###############################################################
#  Generated by:      Cadence Innovus 21.35-s114_1
#  OS:                Linux x86_64(Host ID pc231.ee.hacettepe.edu.tr)
#  Generated on:      Wed Dec 24 10:08:27 2025
#  Design:            mdu_macro
#  Command:           write_lef_abstract -5.7 outputs/mdu_macro/mdu_macro.lef
###############################################################

VERSION 5.7 ;

BUSBITCHARS "[]" ;
DIVIDERCHAR "/" ;

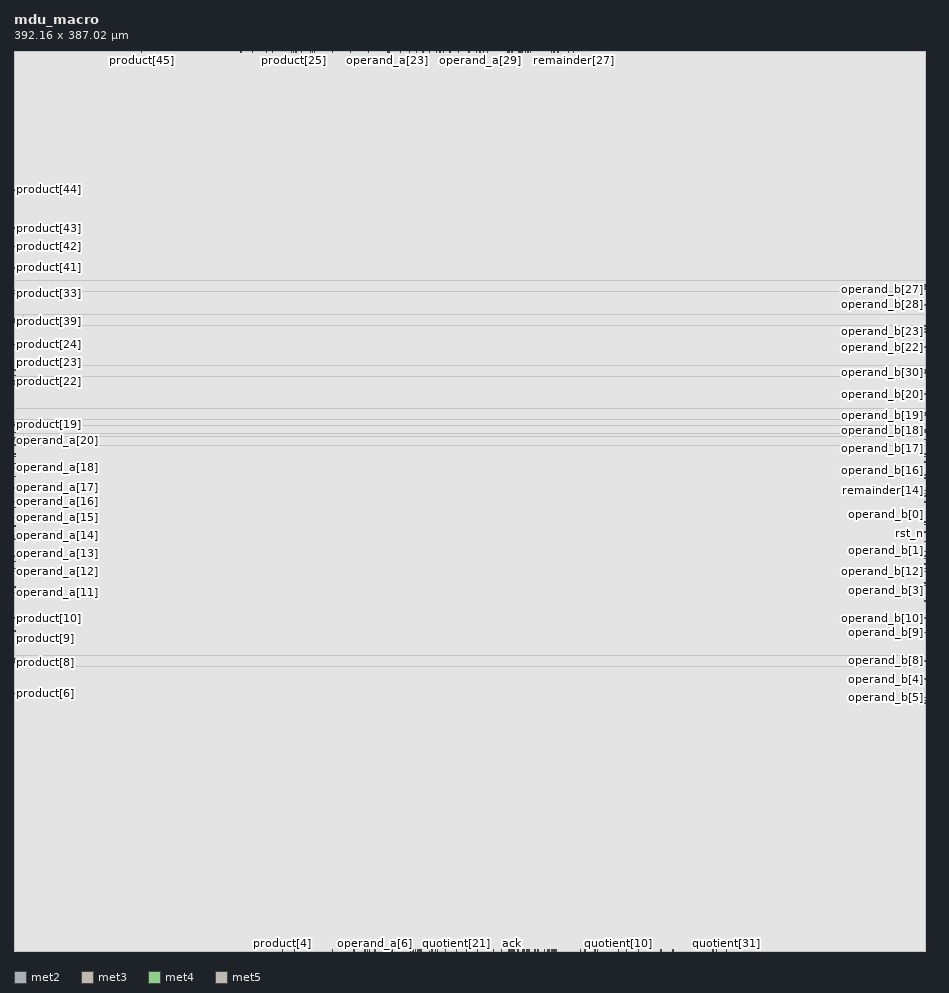
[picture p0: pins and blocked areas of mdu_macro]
MACRO mdu_macro
  CLASS BLOCK ;
  SIZE 392.160000 BY 387.020000 ;
  FOREIGN mdu_macro 0.000000 0.000000 ;
  ORIGIN 0 0 ;
  SYMMETRY X Y R90 ;
  PIN clk
    DIRECTION INPUT ;
    USE SIGNAL ;
    PORT
      LAYER met2 ;
        RECT 203.690000 386.535000 203.830000 387.020000 ;
    END
  END clk
  PIN rst_n
    DIRECTION INPUT ;
    USE SIGNAL ;
    PORT
      LAYER met3 ;
        RECT 391.360000 175.900000 392.160000 176.200000 ;
    END
  END rst_n
  PIN start
    DIRECTION INPUT ;
    USE SIGNAL ;
    PORT
      LAYER met3 ;
        RECT 391.360000 164.310000 392.160000 164.610000 ;
    END
  END start
  PIN ack
    DIRECTION INPUT ;
    USE SIGNAL ;
    PORT
      LAYER met2 ;
        RECT 214.250000 0.000000 214.390000 0.485000 ;
    END
  END ack
  PIN funct3[2]
    DIRECTION INPUT ;
    USE SIGNAL ;
    PORT
      LAYER met3 ;
        RECT 391.360000 180.170000 392.160000 180.470000 ;
    END
  END funct3[2]
  PIN funct3[1]
    DIRECTION INPUT ;
    USE SIGNAL ;
    PORT
      LAYER met3 ;
        RECT 391.360000 196.640000 392.160000 196.940000 ;
    END
  END funct3[1]
  PIN funct3[0]
    DIRECTION INPUT ;
    USE SIGNAL ;
    PORT
      LAYER met3 ;
        RECT 391.360000 195.420000 392.160000 195.720000 ;
    END
  END funct3[0]
  PIN operand_a[31]
    DIRECTION INPUT ;
    USE SIGNAL ;
    PORT
      LAYER met2 ;
        RECT 213.770000 386.535000 213.910000 387.020000 ;
    END
  END operand_a[31]
  PIN operand_a[30]
    DIRECTION INPUT ;
    USE SIGNAL ;
    PORT
      LAYER met2 ;
        RECT 178.730000 386.535000 178.870000 387.020000 ;
    END
  END operand_a[30]
  PIN operand_a[29]
    DIRECTION INPUT ;
    USE SIGNAL ;
    PORT
      LAYER met2 ;
        RECT 200.330000 386.535000 200.470000 387.020000 ;
    END
  END operand_a[29]
  PIN operand_a[28]
    DIRECTION INPUT ;
    USE SIGNAL ;
    PORT
      LAYER met2 ;
        RECT 195.530000 386.535000 195.670000 387.020000 ;
    END
  END operand_a[28]
  PIN operand_a[27]
    DIRECTION INPUT ;
    USE SIGNAL ;
    PORT
      LAYER met2 ;
        RECT 187.370000 386.535000 187.510000 387.020000 ;
    END
  END operand_a[27]
  PIN operand_a[26]
    DIRECTION INPUT ;
    USE SIGNAL ;
    PORT
      LAYER met2 ;
        RECT 183.050000 386.535000 183.190000 387.020000 ;
    END
  END operand_a[26]
  PIN operand_a[25]
    DIRECTION INPUT ;
    USE SIGNAL ;
    PORT
      LAYER met2 ;
        RECT 181.610000 386.535000 181.750000 387.020000 ;
    END
  END operand_a[25]
  PIN operand_a[24]
    DIRECTION INPUT ;
    USE SIGNAL ;
    PORT
      LAYER met2 ;
        RECT 166.250000 386.535000 166.390000 387.020000 ;
    END
  END operand_a[24]
  PIN operand_a[23]
    DIRECTION INPUT ;
    USE SIGNAL ;
    PORT
      LAYER met2 ;
        RECT 160.490000 386.535000 160.630000 387.020000 ;
    END
  END operand_a[23]
  PIN operand_a[22]
    DIRECTION INPUT ;
    USE SIGNAL ;
    PORT
      LAYER met4 ;
        RECT 160.605000 386.220000 160.905000 387.020000 ;
    END
  END operand_a[22]
  PIN operand_a[21]
    DIRECTION INPUT ;
    USE SIGNAL ;
    PORT
      LAYER met3 ;
        RECT 0.000000 225.920000 0.800000 226.220000 ;
    END
  END operand_a[21]
  PIN operand_a[20]
    DIRECTION INPUT ;
    USE SIGNAL ;
    PORT
      LAYER met3 ;
        RECT 0.000000 219.210000 0.800000 219.510000 ;
    END
  END operand_a[20]
  PIN operand_a[19]
    DIRECTION INPUT ;
    USE SIGNAL ;
    PORT
      LAYER met3 ;
        RECT 0.000000 212.500000 0.800000 212.800000 ;
    END
  END operand_a[19]
  PIN operand_a[18]
    DIRECTION INPUT ;
    USE SIGNAL ;
    PORT
      LAYER met3 ;
        RECT 0.000000 207.620000 0.800000 207.920000 ;
    END
  END operand_a[18]
  PIN operand_a[17]
    DIRECTION INPUT ;
    USE SIGNAL ;
    PORT
      LAYER met3 ;
        RECT 0.000000 199.080000 0.800000 199.380000 ;
    END
  END operand_a[17]
  PIN operand_a[16]
    DIRECTION INPUT ;
    USE SIGNAL ;
    PORT
      LAYER met3 ;
        RECT 0.000000 192.980000 0.800000 193.280000 ;
    END
  END operand_a[16]
  PIN operand_a[15]
    DIRECTION INPUT ;
    USE SIGNAL ;
    PORT
      LAYER met3 ;
        RECT 0.000000 186.270000 0.800000 186.570000 ;
    END
  END operand_a[15]
  PIN operand_a[14]
    DIRECTION INPUT ;
    USE SIGNAL ;
    PORT
      LAYER met3 ;
        RECT 0.000000 178.340000 0.800000 178.640000 ;
    END
  END operand_a[14]
  PIN operand_a[13]
    DIRECTION INPUT ;
    USE SIGNAL ;
    PORT
      LAYER met3 ;
        RECT 0.000000 167.360000 0.800000 167.660000 ;
    END
  END operand_a[13]
  PIN operand_a[12]
    DIRECTION INPUT ;
    USE SIGNAL ;
    PORT
      LAYER met3 ;
        RECT 0.000000 163.090000 0.800000 163.390000 ;
    END
  END operand_a[12]
  PIN operand_a[11]
    DIRECTION INPUT ;
    USE SIGNAL ;
    PORT
      LAYER met3 ;
        RECT 0.000000 153.940000 0.800000 154.240000 ;
    END
  END operand_a[11]
  PIN operand_a[10]
    DIRECTION INPUT ;
    USE SIGNAL ;
    PORT
      LAYER met2 ;
        RECT 151.850000 0.000000 151.990000 0.485000 ;
    END
  END operand_a[10]
  PIN operand_a[9]
    DIRECTION INPUT ;
    USE SIGNAL ;
    PORT
      LAYER met2 ;
        RECT 150.890000 0.000000 151.030000 0.485000 ;
    END
  END operand_a[9]
  PIN operand_a[8]
    DIRECTION INPUT ;
    USE SIGNAL ;
    PORT
      LAYER met2 ;
        RECT 159.530000 0.000000 159.670000 0.485000 ;
    END
  END operand_a[8]
  PIN operand_a[7]
    DIRECTION INPUT ;
    USE SIGNAL ;
    PORT
      LAYER met2 ;
        RECT 152.810000 0.000000 152.950000 0.485000 ;
    END
  END operand_a[7]
  PIN operand_a[6]
    DIRECTION INPUT ;
    USE SIGNAL ;
    PORT
      LAYER met2 ;
        RECT 155.210000 0.000000 155.350000 0.485000 ;
    END
  END operand_a[6]
  PIN operand_a[5]
    DIRECTION INPUT ;
    USE SIGNAL ;
    PORT
      LAYER met4 ;
        RECT 150.765000 0.000000 151.065000 0.800000 ;
    END
  END operand_a[5]
  PIN operand_a[4]
    DIRECTION INPUT ;
    USE SIGNAL ;
    PORT
      LAYER met2 ;
        RECT 162.410000 0.000000 162.550000 0.485000 ;
    END
  END operand_a[4]
  PIN operand_a[3]
    DIRECTION INPUT ;
    USE SIGNAL ;
    PORT
      LAYER met2 ;
        RECT 174.890000 0.000000 175.030000 0.485000 ;
    END
  END operand_a[3]
  PIN operand_a[2]
    DIRECTION INPUT ;
    USE SIGNAL ;
    PORT
      LAYER met2 ;
        RECT 181.130000 0.000000 181.270000 0.485000 ;
    END
  END operand_a[2]
  PIN operand_a[1]
    DIRECTION INPUT ;
    USE SIGNAL ;
    PORT
      LAYER met2 ;
        RECT 185.450000 0.000000 185.590000 0.485000 ;
    END
  END operand_a[1]
  PIN operand_a[0]
    DIRECTION INPUT ;
    USE SIGNAL ;
    PORT
      LAYER met2 ;
        RECT 194.570000 0.000000 194.710000 0.485000 ;
    END
  END operand_a[0]
  PIN operand_b[31]
    DIRECTION INPUT ;
    USE SIGNAL ;
    PORT
      LAYER met3 ;
        RECT 391.360000 219.820000 392.160000 220.120000 ;
    END
  END operand_b[31]
  PIN operand_b[30]
    DIRECTION INPUT ;
    USE SIGNAL ;
    PORT
      LAYER met3 ;
        RECT 391.360000 248.490000 392.160000 248.790000 ;
    END
  END operand_b[30]
  PIN operand_b[29]
    DIRECTION INPUT ;
    USE SIGNAL ;
    PORT
      LAYER met3 ;
        RECT 391.360000 267.400000 392.160000 267.700000 ;
    END
  END operand_b[29]
  PIN operand_b[28]
    DIRECTION INPUT ;
    USE SIGNAL ;
    PORT
      LAYER met3 ;
        RECT 391.360000 277.770000 392.160000 278.070000 ;
    END
  END operand_b[28]
  PIN operand_b[27]
    DIRECTION INPUT ;
    USE SIGNAL ;
    PORT
      LAYER met3 ;
        RECT 391.360000 284.480000 392.160000 284.780000 ;
    END
  END operand_b[27]
  PIN operand_b[26]
    DIRECTION INPUT ;
    USE SIGNAL ;
    PORT
      LAYER met3 ;
        RECT 391.360000 285.700000 392.160000 286.000000 ;
    END
  END operand_b[26]
  PIN operand_b[25]
    DIRECTION INPUT ;
    USE SIGNAL ;
    PORT
      LAYER met5 ;
        RECT 389.660000 285.050000 392.160000 286.650000 ;
    END
  END operand_b[25]
  PIN operand_b[24]
    DIRECTION INPUT ;
    USE SIGNAL ;
    PORT
      LAYER met3 ;
        RECT 391.360000 268.620000 392.160000 268.920000 ;
    END
  END operand_b[24]
  PIN operand_b[23]
    DIRECTION INPUT ;
    USE SIGNAL ;
    PORT
      LAYER met3 ;
        RECT 391.360000 266.180000 392.160000 266.480000 ;
    END
  END operand_b[23]
  PIN operand_b[22]
    DIRECTION INPUT ;
    USE SIGNAL ;
    PORT
      LAYER met3 ;
        RECT 391.360000 259.470000 392.160000 259.770000 ;
    END
  END operand_b[22]
  PIN operand_b[21]
    DIRECTION INPUT ;
    USE SIGNAL ;
    PORT
      LAYER met5 ;
        RECT 389.660000 248.450000 392.160000 250.050000 ;
    END
  END operand_b[21]
  PIN operand_b[20]
    DIRECTION INPUT ;
    USE SIGNAL ;
    PORT
      LAYER met3 ;
        RECT 391.360000 239.340000 392.160000 239.640000 ;
    END
  END operand_b[20]
  PIN operand_b[19]
    DIRECTION INPUT ;
    USE SIGNAL ;
    PORT
      LAYER met3 ;
        RECT 391.360000 230.190000 392.160000 230.490000 ;
    END
  END operand_b[19]
  PIN operand_b[18]
    DIRECTION INPUT ;
    USE SIGNAL ;
    PORT
      LAYER met3 ;
        RECT 391.360000 223.480000 392.160000 223.780000 ;
    END
  END operand_b[18]
  PIN operand_b[17]
    DIRECTION INPUT ;
    USE SIGNAL ;
    PORT
      LAYER met3 ;
        RECT 391.360000 212.500000 392.160000 212.800000 ;
    END
  END operand_b[17]
  PIN operand_b[16]
    DIRECTION INPUT ;
    USE SIGNAL ;
    PORT
      LAYER met3 ;
        RECT 391.360000 203.350000 392.160000 203.650000 ;
    END
  END operand_b[16]
  PIN operand_b[15]
    DIRECTION INPUT ;
    USE SIGNAL ;
    PORT
      LAYER met3 ;
        RECT 391.360000 192.980000 392.160000 193.280000 ;
    END
  END operand_b[15]
  PIN operand_b[14]
    DIRECTION INPUT ;
    USE SIGNAL ;
    PORT
      LAYER met3 ;
        RECT 391.360000 183.220000 392.160000 183.520000 ;
    END
  END operand_b[14]
  PIN operand_b[13]
    DIRECTION INPUT ;
    USE SIGNAL ;
    PORT
      LAYER met3 ;
        RECT 391.360000 171.630000 392.160000 171.930000 ;
    END
  END operand_b[13]
  PIN operand_b[12]
    DIRECTION INPUT ;
    USE SIGNAL ;
    PORT
      LAYER met3 ;
        RECT 391.360000 163.090000 392.160000 163.390000 ;
    END
  END operand_b[12]
  PIN operand_b[11]
    DIRECTION INPUT ;
    USE SIGNAL ;
    PORT
      LAYER met3 ;
        RECT 391.360000 150.280000 392.160000 150.580000 ;
    END
  END operand_b[11]
  PIN operand_b[10]
    DIRECTION INPUT ;
    USE SIGNAL ;
    PORT
      LAYER met3 ;
        RECT 391.360000 142.960000 392.160000 143.260000 ;
    END
  END operand_b[10]
  PIN operand_b[9]
    DIRECTION INPUT ;
    USE SIGNAL ;
    PORT
      LAYER met3 ;
        RECT 391.360000 136.860000 392.160000 137.160000 ;
    END
  END operand_b[9]
  PIN operand_b[8]
    DIRECTION INPUT ;
    USE SIGNAL ;
    PORT
      LAYER met3 ;
        RECT 391.360000 124.660000 392.160000 124.960000 ;
    END
  END operand_b[8]
  PIN operand_b[7]
    DIRECTION INPUT ;
    USE SIGNAL ;
    PORT
      LAYER met3 ;
        RECT 391.360000 107.580000 392.160000 107.880000 ;
    END
  END operand_b[7]
  PIN operand_b[6]
    DIRECTION INPUT ;
    USE SIGNAL ;
    PORT
      LAYER met3 ;
        RECT 391.360000 106.360000 392.160000 106.660000 ;
    END
  END operand_b[6]
  PIN operand_b[5]
    DIRECTION INPUT ;
    USE SIGNAL ;
    PORT
      LAYER met3 ;
        RECT 391.360000 108.800000 392.160000 109.100000 ;
    END
  END operand_b[5]
  PIN operand_b[4]
    DIRECTION INPUT ;
    USE SIGNAL ;
    PORT
      LAYER met3 ;
        RECT 391.360000 116.730000 392.160000 117.030000 ;
    END
  END operand_b[4]
  PIN operand_b[3]
    DIRECTION INPUT ;
    USE SIGNAL ;
    PORT
      LAYER met3 ;
        RECT 391.360000 158.210000 392.160000 158.510000 ;
    END
  END operand_b[3]
  PIN operand_b[2]
    DIRECTION INPUT ;
    USE SIGNAL ;
    PORT
      LAYER met3 ;
        RECT 391.360000 166.140000 392.160000 166.440000 ;
    END
  END operand_b[2]
  PIN operand_b[1]
    DIRECTION INPUT ;
    USE SIGNAL ;
    PORT
      LAYER met3 ;
        RECT 391.360000 168.580000 392.160000 168.880000 ;
    END
  END operand_b[1]
  PIN operand_b[0]
    DIRECTION INPUT ;
    USE SIGNAL ;
    PORT
      LAYER met3 ;
        RECT 391.360000 184.440000 392.160000 184.740000 ;
    END
  END operand_b[0]
  PIN busy
    DIRECTION OUTPUT ;
    USE SIGNAL ;
    PORT
      LAYER met4 ;
        RECT 216.570000 0.000000 216.870000 0.800000 ;
    END
  END busy
  PIN done
    DIRECTION OUTPUT ;
    USE SIGNAL ;
    PORT
      LAYER met4 ;
        RECT 213.495000 0.000000 213.795000 0.800000 ;
    END
  END done
  PIN product[63]
    DIRECTION OUTPUT ;
    USE SIGNAL ;
    PORT
      LAYER met2 ;
        RECT 184.490000 386.535000 184.630000 387.020000 ;
    END
  END product[63]
  PIN product[62]
    DIRECTION OUTPUT ;
    USE SIGNAL ;
    PORT
      LAYER met2 ;
        RECT 201.770000 386.535000 201.910000 387.020000 ;
    END
  END product[62]
  PIN product[61]
    DIRECTION OUTPUT ;
    USE SIGNAL ;
    PORT
      LAYER met2 ;
        RECT 212.810000 386.535000 212.950000 387.020000 ;
    END
  END product[61]
  PIN product[60]
    DIRECTION OUTPUT ;
    USE SIGNAL ;
    PORT
      LAYER met4 ;
        RECT 212.265000 386.220000 212.565000 387.020000 ;
    END
  END product[60]
  PIN product[59]
    DIRECTION OUTPUT ;
    USE SIGNAL ;
    PORT
      LAYER met2 ;
        RECT 220.970000 386.535000 221.110000 387.020000 ;
    END
  END product[59]
  PIN product[58]
    DIRECTION OUTPUT ;
    USE SIGNAL ;
    PORT
      LAYER met2 ;
        RECT 217.130000 386.535000 217.270000 387.020000 ;
    END
  END product[58]
  PIN product[57]
    DIRECTION OUTPUT ;
    USE SIGNAL ;
    PORT
      LAYER met2 ;
        RECT 198.890000 386.535000 199.030000 387.020000 ;
    END
  END product[57]
  PIN product[56]
    DIRECTION OUTPUT ;
    USE SIGNAL ;
    PORT
      LAYER met2 ;
        RECT 191.210000 386.535000 191.350000 387.020000 ;
    END
  END product[56]
  PIN product[55]
    DIRECTION OUTPUT ;
    USE SIGNAL ;
    PORT
      LAYER met2 ;
        RECT 175.850000 386.535000 175.990000 387.020000 ;
    END
  END product[55]
  PIN product[54]
    DIRECTION OUTPUT ;
    USE SIGNAL ;
    PORT
      LAYER met2 ;
        RECT 129.290000 386.535000 129.430000 387.020000 ;
    END
  END product[54]
  PIN product[53]
    DIRECTION OUTPUT ;
    USE SIGNAL ;
    PORT
      LAYER met2 ;
        RECT 144.650000 386.535000 144.790000 387.020000 ;
    END
  END product[53]
  PIN product[52]
    DIRECTION OUTPUT ;
    USE SIGNAL ;
    PORT
      LAYER met2 ;
        RECT 136.970000 386.535000 137.110000 387.020000 ;
    END
  END product[52]
  PIN product[51]
    DIRECTION OUTPUT ;
    USE SIGNAL ;
    PORT
      LAYER met2 ;
        RECT 127.370000 386.535000 127.510000 387.020000 ;
    END
  END product[51]
  PIN product[50]
    DIRECTION OUTPUT ;
    USE SIGNAL ;
    PORT
      LAYER met2 ;
        RECT 119.210000 386.535000 119.350000 387.020000 ;
    END
  END product[50]
  PIN product[49]
    DIRECTION OUTPUT ;
    USE SIGNAL ;
    PORT
      LAYER met2 ;
        RECT 121.130000 386.535000 121.270000 387.020000 ;
    END
  END product[49]
  PIN product[48]
    DIRECTION OUTPUT ;
    USE SIGNAL ;
    PORT
      LAYER met2 ;
        RECT 97.610000 386.535000 97.750000 387.020000 ;
    END
  END product[48]
  PIN product[47]
    DIRECTION OUTPUT ;
    USE SIGNAL ;
    PORT
      LAYER met2 ;
        RECT 111.050000 386.535000 111.190000 387.020000 ;
    END
  END product[47]
  PIN product[46]
    DIRECTION OUTPUT ;
    USE SIGNAL ;
    PORT
      LAYER met2 ;
        RECT 102.410000 386.535000 102.550000 387.020000 ;
    END
  END product[46]
  PIN product[45]
    DIRECTION OUTPUT ;
    USE SIGNAL ;
    PORT
      LAYER met2 ;
        RECT 54.890000 386.535000 55.030000 387.020000 ;
    END
  END product[45]
  PIN product[44]
    DIRECTION OUTPUT ;
    USE SIGNAL ;
    PORT
      LAYER met3 ;
        RECT 0.000000 327.180000 0.800000 327.480000 ;
    END
  END product[44]
  PIN product[43]
    DIRECTION OUTPUT ;
    USE SIGNAL ;
    PORT
      LAYER met3 ;
        RECT 0.000000 310.710000 0.800000 311.010000 ;
    END
  END product[43]
  PIN product[42]
    DIRECTION OUTPUT ;
    USE SIGNAL ;
    PORT
      LAYER met3 ;
        RECT 0.000000 302.780000 0.800000 303.080000 ;
    END
  END product[42]
  PIN product[41]
    DIRECTION OUTPUT ;
    USE SIGNAL ;
    PORT
      LAYER met3 ;
        RECT 0.000000 293.630000 0.800000 293.930000 ;
    END
  END product[41]
  PIN product[40]
    DIRECTION OUTPUT ;
    USE SIGNAL ;
    PORT
      LAYER met3 ;
        RECT 0.000000 283.870000 0.800000 284.170000 ;
    END
  END product[40]
  PIN product[39]
    DIRECTION OUTPUT ;
    USE SIGNAL ;
    PORT
      LAYER met3 ;
        RECT 0.000000 270.450000 0.800000 270.750000 ;
    END
  END product[39]
  PIN product[38]
    DIRECTION OUTPUT ;
    USE SIGNAL ;
    PORT
      LAYER met3 ;
        RECT 0.000000 247.270000 0.800000 247.570000 ;
    END
  END product[38]
  PIN product[37]
    DIRECTION OUTPUT ;
    USE SIGNAL ;
    PORT
      LAYER met5 ;
        RECT 0.000000 219.170000 2.500000 220.770000 ;
    END
  END product[37]
  PIN product[36]
    DIRECTION OUTPUT ;
    USE SIGNAL ;
    PORT
      LAYER met3 ;
        RECT 0.000000 213.720000 0.800000 214.020000 ;
    END
  END product[36]
  PIN product[35]
    DIRECTION OUTPUT ;
    USE SIGNAL ;
    PORT
      LAYER met3 ;
        RECT 0.000000 243.610000 0.800000 243.910000 ;
    END
  END product[35]
  PIN product[34]
    DIRECTION OUTPUT ;
    USE SIGNAL ;
    PORT
      LAYER met5 ;
        RECT 0.000000 270.410000 2.500000 272.010000 ;
    END
  END product[34]
  PIN product[33]
    DIRECTION OUTPUT ;
    USE SIGNAL ;
    PORT
      LAYER met3 ;
        RECT 0.000000 282.650000 0.800000 282.950000 ;
    END
  END product[33]
  PIN product[32]
    DIRECTION OUTPUT ;
    USE SIGNAL ;
    PORT
      LAYER met2 ;
        RECT 108.650000 386.535000 108.790000 387.020000 ;
    END
  END product[32]
  PIN product[31]
    DIRECTION OUTPUT ;
    USE SIGNAL ;
    PORT
      LAYER met2 ;
        RECT 123.530000 386.535000 123.670000 387.020000 ;
    END
  END product[31]
  PIN product[30]
    DIRECTION OUTPUT ;
    USE SIGNAL ;
    PORT
      LAYER met2 ;
        RECT 128.330000 386.535000 128.470000 387.020000 ;
    END
  END product[30]
  PIN product[29]
    DIRECTION OUTPUT ;
    USE SIGNAL ;
    PORT
      LAYER met2 ;
        RECT 161.450000 386.535000 161.590000 387.020000 ;
    END
  END product[29]
  PIN product[28]
    DIRECTION OUTPUT ;
    USE SIGNAL ;
    PORT
      LAYER met2 ;
        RECT 172.970000 386.535000 173.110000 387.020000 ;
    END
  END product[28]
  PIN product[27]
    DIRECTION OUTPUT ;
    USE SIGNAL ;
    PORT
      LAYER met2 ;
        RECT 170.090000 386.535000 170.230000 387.020000 ;
    END
  END product[27]
  PIN product[26]
    DIRECTION OUTPUT ;
    USE SIGNAL ;
    PORT
      LAYER met2 ;
        RECT 152.330000 386.535000 152.470000 387.020000 ;
    END
  END product[26]
  PIN product[25]
    DIRECTION OUTPUT ;
    USE SIGNAL ;
    PORT
      LAYER met2 ;
        RECT 120.170000 386.535000 120.310000 387.020000 ;
    END
  END product[25]
  PIN product[24]
    DIRECTION OUTPUT ;
    USE SIGNAL ;
    PORT
      LAYER met3 ;
        RECT 0.000000 260.690000 0.800000 260.990000 ;
    END
  END product[24]
  PIN product[23]
    DIRECTION OUTPUT ;
    USE SIGNAL ;
    PORT
      LAYER met3 ;
        RECT 0.000000 249.710000 0.800000 250.010000 ;
    END
  END product[23]
  PIN product[22]
    DIRECTION OUTPUT ;
    USE SIGNAL ;
    PORT
      LAYER met3 ;
        RECT 0.000000 244.830000 0.800000 245.130000 ;
    END
  END product[22]
  PIN product[21]
    DIRECTION OUTPUT ;
    USE SIGNAL ;
    PORT
      LAYER met3 ;
        RECT 0.000000 227.140000 0.800000 227.440000 ;
    END
  END product[21]
  PIN product[20]
    DIRECTION OUTPUT ;
    USE SIGNAL ;
    PORT
      LAYER met3 ;
        RECT 0.000000 217.380000 0.800000 217.680000 ;
    END
  END product[20]
  PIN product[19]
    DIRECTION OUTPUT ;
    USE SIGNAL ;
    PORT
      LAYER met3 ;
        RECT 0.000000 222.870000 0.800000 223.170000 ;
    END
  END product[19]
  PIN product[18]
    DIRECTION OUTPUT ;
    USE SIGNAL ;
    PORT
      LAYER met3 ;
        RECT 0.000000 209.450000 0.800000 209.750000 ;
    END
  END product[18]
  PIN product[17]
    DIRECTION OUTPUT ;
    USE SIGNAL ;
    PORT
      LAYER met3 ;
        RECT 0.000000 203.960000 0.800000 204.260000 ;
    END
  END product[17]
  PIN product[16]
    DIRECTION OUTPUT ;
    USE SIGNAL ;
    PORT
      LAYER met3 ;
        RECT 0.000000 190.540000 0.800000 190.840000 ;
    END
  END product[16]
  PIN product[15]
    DIRECTION OUTPUT ;
    USE SIGNAL ;
    PORT
      LAYER met3 ;
        RECT 0.000000 182.610000 0.800000 182.910000 ;
    END
  END product[15]
  PIN product[14]
    DIRECTION OUTPUT ;
    USE SIGNAL ;
    PORT
      LAYER met3 ;
        RECT 0.000000 177.120000 0.800000 177.420000 ;
    END
  END product[14]
  PIN product[13]
    DIRECTION OUTPUT ;
    USE SIGNAL ;
    PORT
      LAYER met3 ;
        RECT 0.000000 169.800000 0.800000 170.100000 ;
    END
  END product[13]
  PIN product[12]
    DIRECTION OUTPUT ;
    USE SIGNAL ;
    PORT
      LAYER met3 ;
        RECT 0.000000 164.310000 0.800000 164.610000 ;
    END
  END product[12]
  PIN product[11]
    DIRECTION OUTPUT ;
    USE SIGNAL ;
    PORT
      LAYER met3 ;
        RECT 0.000000 156.380000 0.800000 156.680000 ;
    END
  END product[11]
  PIN product[10]
    DIRECTION OUTPUT ;
    USE SIGNAL ;
    PORT
      LAYER met3 ;
        RECT 0.000000 142.960000 0.800000 143.260000 ;
    END
  END product[10]
  PIN product[9]
    DIRECTION OUTPUT ;
    USE SIGNAL ;
    PORT
      LAYER met3 ;
        RECT 0.000000 137.470000 0.800000 137.770000 ;
    END
  END product[9]
  PIN product[8]
    DIRECTION OUTPUT ;
    USE SIGNAL ;
    PORT
      LAYER met3 ;
        RECT 0.000000 124.050000 0.800000 124.350000 ;
    END
  END product[8]
  PIN product[7]
    DIRECTION OUTPUT ;
    USE SIGNAL ;
    PORT
      LAYER met5 ;
        RECT 0.000000 124.010000 2.500000 125.610000 ;
    END
  END product[7]
  PIN product[6]
    DIRECTION OUTPUT ;
    USE SIGNAL ;
    PORT
      LAYER met3 ;
        RECT 0.000000 110.630000 0.800000 110.930000 ;
    END
  END product[6]
  PIN product[5]
    DIRECTION OUTPUT ;
    USE SIGNAL ;
    PORT
      LAYER met2 ;
        RECT 120.650000 0.000000 120.790000 0.485000 ;
    END
  END product[5]
  PIN product[4]
    DIRECTION OUTPUT ;
    USE SIGNAL ;
    PORT
      LAYER met2 ;
        RECT 115.370000 0.000000 115.510000 0.485000 ;
    END
  END product[4]
  PIN product[3]
    DIRECTION OUTPUT ;
    USE SIGNAL ;
    PORT
      LAYER met2 ;
        RECT 136.970000 0.000000 137.110000 0.485000 ;
    END
  END product[3]
  PIN product[2]
    DIRECTION OUTPUT ;
    USE SIGNAL ;
    PORT
      LAYER met2 ;
        RECT 146.090000 0.000000 146.230000 0.485000 ;
    END
  END product[2]
  PIN product[1]
    DIRECTION OUTPUT ;
    USE SIGNAL ;
    PORT
      LAYER met4 ;
        RECT 162.450000 0.000000 162.750000 0.800000 ;
    END
  END product[1]
  PIN product[0]
    DIRECTION OUTPUT ;
    USE SIGNAL ;
    PORT
      LAYER met2 ;
        RECT 172.490000 0.000000 172.630000 0.485000 ;
    END
  END product[0]
  PIN quotient[31]
    DIRECTION OUTPUT ;
    USE SIGNAL ;
    PORT
      LAYER met2 ;
        RECT 306.410000 0.000000 306.550000 0.485000 ;
    END
  END quotient[31]
  PIN quotient[30]
    DIRECTION OUTPUT ;
    USE SIGNAL ;
    PORT
      LAYER met2 ;
        RECT 302.090000 0.000000 302.230000 0.485000 ;
    END
  END quotient[30]
  PIN quotient[29]
    DIRECTION OUTPUT ;
    USE SIGNAL ;
    PORT
      LAYER met2 ;
        RECT 283.370000 0.000000 283.510000 0.485000 ;
    END
  END quotient[29]
  PIN quotient[28]
    DIRECTION OUTPUT ;
    USE SIGNAL ;
    PORT
      LAYER met2 ;
        RECT 278.090000 0.000000 278.230000 0.485000 ;
    END
  END quotient[28]
  PIN quotient[27]
    DIRECTION OUTPUT ;
    USE SIGNAL ;
    PORT
      LAYER met2 ;
        RECT 263.210000 0.000000 263.350000 0.485000 ;
    END
  END quotient[27]
  PIN quotient[26]
    DIRECTION OUTPUT ;
    USE SIGNAL ;
    PORT
      LAYER met2 ;
        RECT 245.450000 0.000000 245.590000 0.485000 ;
    END
  END quotient[26]
  PIN quotient[25]
    DIRECTION OUTPUT ;
    USE SIGNAL ;
    PORT
      LAYER met2 ;
        RECT 232.010000 0.000000 232.150000 0.485000 ;
    END
  END quotient[25]
  PIN quotient[24]
    DIRECTION OUTPUT ;
    USE SIGNAL ;
    PORT
      LAYER met2 ;
        RECT 218.570000 0.000000 218.710000 0.485000 ;
    END
  END quotient[24]
  PIN quotient[23]
    DIRECTION OUTPUT ;
    USE SIGNAL ;
    PORT
      LAYER met2 ;
        RECT 215.210000 0.000000 215.350000 0.485000 ;
    END
  END quotient[23]
  PIN quotient[22]
    DIRECTION OUTPUT ;
    USE SIGNAL ;
    PORT
      LAYER met2 ;
        RECT 199.370000 0.000000 199.510000 0.485000 ;
    END
  END quotient[22]
  PIN quotient[21]
    DIRECTION OUTPUT ;
    USE SIGNAL ;
    PORT
      LAYER met2 ;
        RECT 190.250000 0.000000 190.390000 0.485000 ;
    END
  END quotient[21]
  PIN quotient[20]
    DIRECTION OUTPUT ;
    USE SIGNAL ;
    PORT
      LAYER met2 ;
        RECT 170.570000 0.000000 170.710000 0.485000 ;
    END
  END quotient[20]
  PIN quotient[19]
    DIRECTION OUTPUT ;
    USE SIGNAL ;
    PORT
      LAYER met2 ;
        RECT 171.530000 0.000000 171.670000 0.485000 ;
    END
  END quotient[19]
  PIN quotient[18]
    DIRECTION OUTPUT ;
    USE SIGNAL ;
    PORT
      LAYER met2 ;
        RECT 178.730000 0.000000 178.870000 0.485000 ;
    END
  END quotient[18]
  PIN quotient[17]
    DIRECTION OUTPUT ;
    USE SIGNAL ;
    PORT
      LAYER met4 ;
        RECT 214.725000 0.000000 215.025000 0.800000 ;
    END
  END quotient[17]
  PIN quotient[16]
    DIRECTION OUTPUT ;
    USE SIGNAL ;
    PORT
      LAYER met2 ;
        RECT 232.970000 0.000000 233.110000 0.485000 ;
    END
  END quotient[16]
  PIN quotient[15]
    DIRECTION OUTPUT ;
    USE SIGNAL ;
    PORT
      LAYER met2 ;
        RECT 250.730000 0.000000 250.870000 0.485000 ;
    END
  END quotient[15]
  PIN quotient[14]
    DIRECTION OUTPUT ;
    USE SIGNAL ;
    PORT
      LAYER met2 ;
        RECT 268.490000 0.000000 268.630000 0.485000 ;
    END
  END quotient[14]
  PIN quotient[13]
    DIRECTION OUTPUT ;
    USE SIGNAL ;
    PORT
      LAYER met2 ;
        RECT 300.650000 0.000000 300.790000 0.485000 ;
    END
  END quotient[13]
  PIN quotient[12]
    DIRECTION OUTPUT ;
    USE SIGNAL ;
    PORT
      LAYER met4 ;
        RECT 300.210000 0.000000 300.510000 0.800000 ;
    END
  END quotient[12]
  PIN quotient[11]
    DIRECTION OUTPUT ;
    USE SIGNAL ;
    PORT
      LAYER met4 ;
        RECT 278.070000 0.000000 278.370000 0.800000 ;
    END
  END quotient[11]
  PIN quotient[10]
    DIRECTION OUTPUT ;
    USE SIGNAL ;
    PORT
      LAYER met2 ;
        RECT 259.850000 0.000000 259.990000 0.485000 ;
    END
  END quotient[10]
  PIN quotient[9]
    DIRECTION OUTPUT ;
    USE SIGNAL ;
    PORT
      LAYER met2 ;
        RECT 249.770000 0.000000 249.910000 0.485000 ;
    END
  END quotient[9]
  PIN quotient[8]
    DIRECTION OUTPUT ;
    USE SIGNAL ;
    PORT
      LAYER met2 ;
        RECT 243.530000 0.000000 243.670000 0.485000 ;
    END
  END quotient[8]
  PIN quotient[7]
    DIRECTION OUTPUT ;
    USE SIGNAL ;
    PORT
      LAYER met2 ;
        RECT 229.610000 0.000000 229.750000 0.485000 ;
    END
  END quotient[7]
  PIN quotient[6]
    DIRECTION OUTPUT ;
    USE SIGNAL ;
    PORT
      LAYER met2 ;
        RECT 221.450000 0.000000 221.590000 0.485000 ;
    END
  END quotient[6]
  PIN quotient[5]
    DIRECTION OUTPUT ;
    USE SIGNAL ;
    PORT
      LAYER met2 ;
        RECT 182.090000 0.000000 182.230000 0.485000 ;
    END
  END quotient[5]
  PIN quotient[4]
    DIRECTION OUTPUT ;
    USE SIGNAL ;
    PORT
      LAYER met4 ;
        RECT 174.135000 0.000000 174.435000 0.800000 ;
    END
  END quotient[4]
  PIN quotient[3]
    DIRECTION OUTPUT ;
    USE SIGNAL ;
    PORT
      LAYER met2 ;
        RECT 179.690000 0.000000 179.830000 0.485000 ;
    END
  END quotient[3]
  PIN quotient[2]
    DIRECTION OUTPUT ;
    USE SIGNAL ;
    PORT
      LAYER met2 ;
        RECT 173.450000 0.000000 173.590000 0.485000 ;
    END
  END quotient[2]
  PIN quotient[1]
    DIRECTION OUTPUT ;
    USE SIGNAL ;
    PORT
      LAYER met2 ;
        RECT 223.850000 0.000000 223.990000 0.485000 ;
    END
  END quotient[1]
  PIN quotient[0]
    DIRECTION OUTPUT ;
    USE SIGNAL ;
    PORT
      LAYER met4 ;
        RECT 223.950000 0.000000 224.250000 0.800000 ;
    END
  END quotient[0]
  PIN remainder[31]
    DIRECTION OUTPUT ;
    USE SIGNAL ;
    PORT
      LAYER met2 ;
        RECT 233.930000 386.535000 234.070000 387.020000 ;
    END
  END remainder[31]
  PIN remainder[30]
    DIRECTION OUTPUT ;
    USE SIGNAL ;
    PORT
      LAYER met2 ;
        RECT 232.010000 386.535000 232.150000 387.020000 ;
    END
  END remainder[30]
  PIN remainder[29]
    DIRECTION OUTPUT ;
    USE SIGNAL ;
    PORT
      LAYER met2 ;
        RECT 238.250000 386.535000 238.390000 387.020000 ;
    END
  END remainder[29]
  PIN remainder[28]
    DIRECTION OUTPUT ;
    USE SIGNAL ;
    PORT
      LAYER met2 ;
        RECT 231.050000 386.535000 231.190000 387.020000 ;
    END
  END remainder[28]
  PIN remainder[27]
    DIRECTION OUTPUT ;
    USE SIGNAL ;
    PORT
      LAYER met2 ;
        RECT 240.650000 386.535000 240.790000 387.020000 ;
    END
  END remainder[27]
  PIN remainder[26]
    DIRECTION OUTPUT ;
    USE SIGNAL ;
    PORT
      LAYER met4 ;
        RECT 220.875000 386.220000 221.175000 387.020000 ;
    END
  END remainder[26]
  PIN remainder[25]
    DIRECTION OUTPUT ;
    USE SIGNAL ;
    PORT
      LAYER met4 ;
        RECT 214.110000 386.220000 214.410000 387.020000 ;
    END
  END remainder[25]
  PIN remainder[24]
    DIRECTION OUTPUT ;
    USE SIGNAL ;
    PORT
      LAYER met2 ;
        RECT 220.010000 386.535000 220.150000 387.020000 ;
    END
  END remainder[24]
  PIN remainder[23]
    DIRECTION OUTPUT ;
    USE SIGNAL ;
    PORT
      LAYER met2 ;
        RECT 218.570000 386.535000 218.710000 387.020000 ;
    END
  END remainder[23]
  PIN remainder[22]
    DIRECTION OUTPUT ;
    USE SIGNAL ;
    PORT
      LAYER met4 ;
        RECT 217.800000 386.220000 218.100000 387.020000 ;
    END
  END remainder[22]
  PIN remainder[21]
    DIRECTION OUTPUT ;
    USE SIGNAL ;
    PORT
      LAYER met2 ;
        RECT 221.930000 386.535000 222.070000 387.020000 ;
    END
  END remainder[21]
  PIN remainder[20]
    DIRECTION OUTPUT ;
    USE SIGNAL ;
    PORT
      LAYER met4 ;
        RECT 231.945000 386.220000 232.245000 387.020000 ;
    END
  END remainder[20]
  PIN remainder[19]
    DIRECTION OUTPUT ;
    USE SIGNAL ;
    PORT
      LAYER met5 ;
        RECT 389.660000 230.150000 392.160000 231.750000 ;
    END
  END remainder[19]
  PIN remainder[18]
    DIRECTION OUTPUT ;
    USE SIGNAL ;
    PORT
      LAYER met5 ;
        RECT 389.660000 222.830000 392.160000 224.430000 ;
    END
  END remainder[18]
  PIN remainder[17]
    DIRECTION OUTPUT ;
    USE SIGNAL ;
    PORT
      LAYER met3 ;
        RECT 391.360000 213.720000 392.160000 214.020000 ;
    END
  END remainder[17]
  PIN remainder[16]
    DIRECTION OUTPUT ;
    USE SIGNAL ;
    PORT
      LAYER met3 ;
        RECT 391.360000 210.060000 392.160000 210.360000 ;
    END
  END remainder[16]
  PIN remainder[15]
    DIRECTION OUTPUT ;
    USE SIGNAL ;
    PORT
      LAYER met3 ;
        RECT 391.360000 204.570000 392.160000 204.870000 ;
    END
  END remainder[15]
  PIN remainder[14]
    DIRECTION OUTPUT ;
    USE SIGNAL ;
    PORT
      LAYER met3 ;
        RECT 391.360000 197.860000 392.160000 198.160000 ;
    END
  END remainder[14]
  PIN remainder[13]
    DIRECTION OUTPUT ;
    USE SIGNAL ;
    PORT
      LAYER met3 ;
        RECT 391.360000 169.800000 392.160000 170.100000 ;
    END
  END remainder[13]
  PIN remainder[12]
    DIRECTION OUTPUT ;
    USE SIGNAL ;
    PORT
      LAYER met3 ;
        RECT 391.360000 156.990000 392.160000 157.290000 ;
    END
  END remainder[12]
  PIN remainder[11]
    DIRECTION OUTPUT ;
    USE SIGNAL ;
    PORT
      LAYER met4 ;
        RECT 230.100000 0.000000 230.400000 0.800000 ;
    END
  END remainder[11]
  PIN remainder[10]
    DIRECTION OUTPUT ;
    USE SIGNAL ;
    PORT
      LAYER met4 ;
        RECT 219.030000 0.000000 219.330000 0.800000 ;
    END
  END remainder[10]
  PIN remainder[9]
    DIRECTION OUTPUT ;
    USE SIGNAL ;
    PORT
      LAYER met4 ;
        RECT 221.490000 0.000000 221.790000 0.800000 ;
    END
  END remainder[9]
  PIN remainder[8]
    DIRECTION OUTPUT ;
    USE SIGNAL ;
    PORT
      LAYER met2 ;
        RECT 220.490000 0.000000 220.630000 0.485000 ;
    END
  END remainder[8]
  PIN remainder[7]
    DIRECTION OUTPUT ;
    USE SIGNAL ;
    PORT
      LAYER met4 ;
        RECT 231.330000 0.000000 231.630000 0.800000 ;
    END
  END remainder[7]
  PIN remainder[6]
    DIRECTION OUTPUT ;
    USE SIGNAL ;
    PORT
      LAYER met2 ;
        RECT 228.170000 0.000000 228.310000 0.485000 ;
    END
  END remainder[6]
  PIN remainder[5]
    DIRECTION OUTPUT ;
    USE SIGNAL ;
    PORT
      LAYER met2 ;
        RECT 225.290000 0.000000 225.430000 0.485000 ;
    END
  END remainder[5]
  PIN remainder[4]
    DIRECTION OUTPUT ;
    USE SIGNAL ;
    PORT
      LAYER met2 ;
        RECT 216.650000 0.000000 216.790000 0.485000 ;
    END
  END remainder[4]
  PIN remainder[3]
    DIRECTION OUTPUT ;
    USE SIGNAL ;
    PORT
      LAYER met2 ;
        RECT 209.450000 0.000000 209.590000 0.485000 ;
    END
  END remainder[3]
  PIN remainder[2]
    DIRECTION OUTPUT ;
    USE SIGNAL ;
    PORT
      LAYER met2 ;
        RECT 206.090000 0.000000 206.230000 0.485000 ;
    END
  END remainder[2]
  PIN remainder[1]
    DIRECTION OUTPUT ;
    USE SIGNAL ;
    PORT
      LAYER met2 ;
        RECT 212.810000 0.000000 212.950000 0.485000 ;
    END
  END remainder[1]
  PIN remainder[0]
    DIRECTION OUTPUT ;
    USE SIGNAL ;
    PORT
      LAYER met4 ;
        RECT 232.560000 0.000000 232.860000 0.800000 ;
    END
  END remainder[0]
  OBS
    LAYER met1 ;
      RECT 0.000000 0.000000 392.160000 387.020000 ;
    LAYER met2 ;
      RECT 240.930000 386.395000 392.160000 387.020000 ;
      RECT 238.530000 386.395000 240.510000 387.020000 ;
      RECT 234.210000 386.395000 238.110000 387.020000 ;
      RECT 232.290000 386.395000 233.790000 387.020000 ;
      RECT 231.330000 386.395000 231.870000 387.020000 ;
      RECT 222.210000 386.395000 230.910000 387.020000 ;
      RECT 221.250000 386.395000 221.790000 387.020000 ;
      RECT 220.290000 386.395000 220.830000 387.020000 ;
      RECT 218.850000 386.395000 219.870000 387.020000 ;
      RECT 217.410000 386.395000 218.430000 387.020000 ;
      RECT 214.050000 386.395000 216.990000 387.020000 ;
      RECT 213.090000 386.395000 213.630000 387.020000 ;
      RECT 203.970000 386.395000 212.670000 387.020000 ;
      RECT 202.050000 386.395000 203.550000 387.020000 ;
      RECT 200.610000 386.395000 201.630000 387.020000 ;
      RECT 199.170000 386.395000 200.190000 387.020000 ;
      RECT 195.810000 386.395000 198.750000 387.020000 ;
      RECT 191.490000 386.395000 195.390000 387.020000 ;
      RECT 187.650000 386.395000 191.070000 387.020000 ;
      RECT 184.770000 386.395000 187.230000 387.020000 ;
      RECT 183.330000 386.395000 184.350000 387.020000 ;
      RECT 181.890000 386.395000 182.910000 387.020000 ;
      RECT 179.010000 386.395000 181.470000 387.020000 ;
      RECT 176.130000 386.395000 178.590000 387.020000 ;
      RECT 173.250000 386.395000 175.710000 387.020000 ;
      RECT 170.370000 386.395000 172.830000 387.020000 ;
      RECT 166.530000 386.395000 169.950000 387.020000 ;
      RECT 161.730000 386.395000 166.110000 387.020000 ;
      RECT 160.770000 386.395000 161.310000 387.020000 ;
      RECT 152.610000 386.395000 160.350000 387.020000 ;
      RECT 144.930000 386.395000 152.190000 387.020000 ;
      RECT 137.250000 386.395000 144.510000 387.020000 ;
      RECT 129.570000 386.395000 136.830000 387.020000 ;
      RECT 128.610000 386.395000 129.150000 387.020000 ;
      RECT 127.650000 386.395000 128.190000 387.020000 ;
      RECT 123.810000 386.395000 127.230000 387.020000 ;
      RECT 121.410000 386.395000 123.390000 387.020000 ;
      RECT 120.450000 386.395000 120.990000 387.020000 ;
      RECT 119.490000 386.395000 120.030000 387.020000 ;
      RECT 111.330000 386.395000 119.070000 387.020000 ;
      RECT 108.930000 386.395000 110.910000 387.020000 ;
      RECT 102.690000 386.395000 108.510000 387.020000 ;
      RECT 97.890000 386.395000 102.270000 387.020000 ;
      RECT 55.170000 386.395000 97.470000 387.020000 ;
      RECT 0.000000 386.395000 54.750000 387.020000 ;
      RECT 0.000000 0.625000 392.160000 386.395000 ;
      RECT 306.690000 0.000000 392.160000 0.625000 ;
      RECT 302.370000 0.000000 306.270000 0.625000 ;
      RECT 300.930000 0.000000 301.950000 0.625000 ;
      RECT 283.650000 0.000000 300.510000 0.625000 ;
      RECT 278.370000 0.000000 283.230000 0.625000 ;
      RECT 268.770000 0.000000 277.950000 0.625000 ;
      RECT 263.490000 0.000000 268.350000 0.625000 ;
      RECT 260.130000 0.000000 263.070000 0.625000 ;
      RECT 251.010000 0.000000 259.710000 0.625000 ;
      RECT 250.050000 0.000000 250.590000 0.625000 ;
      RECT 245.730000 0.000000 249.630000 0.625000 ;
      RECT 243.810000 0.000000 245.310000 0.625000 ;
      RECT 233.250000 0.000000 243.390000 0.625000 ;
      RECT 232.290000 0.000000 232.830000 0.625000 ;
      RECT 229.890000 0.000000 231.870000 0.625000 ;
      RECT 228.450000 0.000000 229.470000 0.625000 ;
      RECT 225.570000 0.000000 228.030000 0.625000 ;
      RECT 224.130000 0.000000 225.150000 0.625000 ;
      RECT 221.730000 0.000000 223.710000 0.625000 ;
      RECT 220.770000 0.000000 221.310000 0.625000 ;
      RECT 218.850000 0.000000 220.350000 0.625000 ;
      RECT 216.930000 0.000000 218.430000 0.625000 ;
      RECT 215.490000 0.000000 216.510000 0.625000 ;
      RECT 214.530000 0.000000 215.070000 0.625000 ;
      RECT 213.090000 0.000000 214.110000 0.625000 ;
      RECT 209.730000 0.000000 212.670000 0.625000 ;
      RECT 206.370000 0.000000 209.310000 0.625000 ;
      RECT 199.650000 0.000000 205.950000 0.625000 ;
      RECT 194.850000 0.000000 199.230000 0.625000 ;
      RECT 190.530000 0.000000 194.430000 0.625000 ;
      RECT 185.730000 0.000000 190.110000 0.625000 ;
      RECT 182.370000 0.000000 185.310000 0.625000 ;
      RECT 181.410000 0.000000 181.950000 0.625000 ;
      RECT 179.970000 0.000000 180.990000 0.625000 ;
      RECT 179.010000 0.000000 179.550000 0.625000 ;
      RECT 175.170000 0.000000 178.590000 0.625000 ;
      RECT 173.730000 0.000000 174.750000 0.625000 ;
      RECT 172.770000 0.000000 173.310000 0.625000 ;
      RECT 171.810000 0.000000 172.350000 0.625000 ;
      RECT 170.850000 0.000000 171.390000 0.625000 ;
      RECT 162.690000 0.000000 170.430000 0.625000 ;
      RECT 159.810000 0.000000 162.270000 0.625000 ;
      RECT 155.490000 0.000000 159.390000 0.625000 ;
      RECT 153.090000 0.000000 155.070000 0.625000 ;
      RECT 152.130000 0.000000 152.670000 0.625000 ;
      RECT 151.170000 0.000000 151.710000 0.625000 ;
      RECT 146.370000 0.000000 150.750000 0.625000 ;
      RECT 137.250000 0.000000 145.950000 0.625000 ;
      RECT 120.930000 0.000000 136.830000 0.625000 ;
      RECT 115.650000 0.000000 120.510000 0.625000 ;
      RECT 0.000000 0.000000 115.230000 0.625000 ;
    LAYER met3 ;
      RECT 0.000000 327.780000 392.160000 387.020000 ;
      RECT 1.100000 326.880000 392.160000 327.780000 ;
      RECT 0.000000 311.310000 392.160000 326.880000 ;
      RECT 1.100000 310.410000 392.160000 311.310000 ;
      RECT 0.000000 303.380000 392.160000 310.410000 ;
      RECT 1.100000 302.480000 392.160000 303.380000 ;
      RECT 0.000000 294.230000 392.160000 302.480000 ;
      RECT 1.100000 293.330000 392.160000 294.230000 ;
      RECT 0.000000 286.300000 392.160000 293.330000 ;
      RECT 0.000000 285.400000 391.060000 286.300000 ;
      RECT 0.000000 285.080000 392.160000 285.400000 ;
      RECT 0.000000 284.470000 391.060000 285.080000 ;
      RECT 1.100000 284.180000 391.060000 284.470000 ;
      RECT 1.100000 283.570000 392.160000 284.180000 ;
      RECT 0.000000 283.250000 392.160000 283.570000 ;
      RECT 1.100000 282.350000 392.160000 283.250000 ;
      RECT 0.000000 278.370000 392.160000 282.350000 ;
      RECT 0.000000 277.470000 391.060000 278.370000 ;
      RECT 0.000000 271.050000 392.160000 277.470000 ;
      RECT 1.100000 270.150000 392.160000 271.050000 ;
      RECT 0.000000 269.220000 392.160000 270.150000 ;
      RECT 0.000000 268.320000 391.060000 269.220000 ;
      RECT 0.000000 268.000000 392.160000 268.320000 ;
      RECT 0.000000 267.100000 391.060000 268.000000 ;
      RECT 0.000000 266.780000 392.160000 267.100000 ;
      RECT 0.000000 265.880000 391.060000 266.780000 ;
      RECT 0.000000 261.290000 392.160000 265.880000 ;
      RECT 1.100000 260.390000 392.160000 261.290000 ;
      RECT 0.000000 260.070000 392.160000 260.390000 ;
      RECT 0.000000 259.170000 391.060000 260.070000 ;
      RECT 0.000000 250.310000 392.160000 259.170000 ;
      RECT 1.100000 249.410000 392.160000 250.310000 ;
      RECT 0.000000 249.090000 392.160000 249.410000 ;
      RECT 0.000000 248.190000 391.060000 249.090000 ;
      RECT 0.000000 247.870000 392.160000 248.190000 ;
      RECT 1.100000 246.970000 392.160000 247.870000 ;
      RECT 0.000000 245.430000 392.160000 246.970000 ;
      RECT 1.100000 244.530000 392.160000 245.430000 ;
      RECT 0.000000 244.210000 392.160000 244.530000 ;
      RECT 1.100000 243.310000 392.160000 244.210000 ;
      RECT 0.000000 239.940000 392.160000 243.310000 ;
      RECT 0.000000 239.040000 391.060000 239.940000 ;
      RECT 0.000000 230.790000 392.160000 239.040000 ;
      RECT 0.000000 229.890000 391.060000 230.790000 ;
      RECT 0.000000 227.740000 392.160000 229.890000 ;
      RECT 1.100000 226.840000 392.160000 227.740000 ;
      RECT 0.000000 226.520000 392.160000 226.840000 ;
      RECT 1.100000 225.620000 392.160000 226.520000 ;
      RECT 0.000000 224.080000 392.160000 225.620000 ;
      RECT 0.000000 223.470000 391.060000 224.080000 ;
      RECT 1.100000 223.180000 391.060000 223.470000 ;
      RECT 1.100000 222.570000 392.160000 223.180000 ;
      RECT 0.000000 220.420000 392.160000 222.570000 ;
      RECT 0.000000 219.810000 391.060000 220.420000 ;
      RECT 1.100000 219.520000 391.060000 219.810000 ;
      RECT 1.100000 218.910000 392.160000 219.520000 ;
      RECT 0.000000 217.980000 392.160000 218.910000 ;
      RECT 1.100000 217.080000 392.160000 217.980000 ;
      RECT 0.000000 214.320000 392.160000 217.080000 ;
      RECT 1.100000 213.420000 391.060000 214.320000 ;
      RECT 0.000000 213.100000 392.160000 213.420000 ;
      RECT 1.100000 212.200000 391.060000 213.100000 ;
      RECT 0.000000 210.660000 392.160000 212.200000 ;
      RECT 0.000000 210.050000 391.060000 210.660000 ;
      RECT 1.100000 209.760000 391.060000 210.050000 ;
      RECT 1.100000 209.150000 392.160000 209.760000 ;
      RECT 0.000000 208.220000 392.160000 209.150000 ;
      RECT 1.100000 207.320000 392.160000 208.220000 ;
      RECT 0.000000 205.170000 392.160000 207.320000 ;
      RECT 0.000000 204.560000 391.060000 205.170000 ;
      RECT 1.100000 204.270000 391.060000 204.560000 ;
      RECT 1.100000 203.950000 392.160000 204.270000 ;
      RECT 1.100000 203.660000 391.060000 203.950000 ;
      RECT 0.000000 203.050000 391.060000 203.660000 ;
      RECT 0.000000 199.680000 392.160000 203.050000 ;
      RECT 1.100000 198.780000 392.160000 199.680000 ;
      RECT 0.000000 198.460000 392.160000 198.780000 ;
      RECT 0.000000 197.560000 391.060000 198.460000 ;
      RECT 0.000000 197.240000 392.160000 197.560000 ;
      RECT 0.000000 196.340000 391.060000 197.240000 ;
      RECT 0.000000 196.020000 392.160000 196.340000 ;
      RECT 0.000000 195.120000 391.060000 196.020000 ;
      RECT 0.000000 193.580000 392.160000 195.120000 ;
      RECT 1.100000 192.680000 391.060000 193.580000 ;
      RECT 0.000000 191.140000 392.160000 192.680000 ;
      RECT 1.100000 190.240000 392.160000 191.140000 ;
      RECT 0.000000 186.870000 392.160000 190.240000 ;
      RECT 1.100000 185.970000 392.160000 186.870000 ;
      RECT 0.000000 185.040000 392.160000 185.970000 ;
      RECT 0.000000 184.140000 391.060000 185.040000 ;
      RECT 0.000000 183.820000 392.160000 184.140000 ;
      RECT 0.000000 183.210000 391.060000 183.820000 ;
      RECT 1.100000 182.920000 391.060000 183.210000 ;
      RECT 1.100000 182.310000 392.160000 182.920000 ;
      RECT 0.000000 180.770000 392.160000 182.310000 ;
      RECT 0.000000 179.870000 391.060000 180.770000 ;
      RECT 0.000000 178.940000 392.160000 179.870000 ;
      RECT 1.100000 178.040000 392.160000 178.940000 ;
      RECT 0.000000 177.720000 392.160000 178.040000 ;
      RECT 1.100000 176.820000 392.160000 177.720000 ;
      RECT 0.000000 176.500000 392.160000 176.820000 ;
      RECT 0.000000 175.600000 391.060000 176.500000 ;
      RECT 0.000000 172.230000 392.160000 175.600000 ;
      RECT 0.000000 171.330000 391.060000 172.230000 ;
      RECT 0.000000 170.400000 392.160000 171.330000 ;
      RECT 1.100000 169.500000 391.060000 170.400000 ;
      RECT 0.000000 169.180000 392.160000 169.500000 ;
      RECT 0.000000 168.280000 391.060000 169.180000 ;
      RECT 0.000000 167.960000 392.160000 168.280000 ;
      RECT 1.100000 167.060000 392.160000 167.960000 ;
      RECT 0.000000 166.740000 392.160000 167.060000 ;
      RECT 0.000000 165.840000 391.060000 166.740000 ;
      RECT 0.000000 164.910000 392.160000 165.840000 ;
      RECT 1.100000 164.010000 391.060000 164.910000 ;
      RECT 0.000000 163.690000 392.160000 164.010000 ;
      RECT 1.100000 162.790000 391.060000 163.690000 ;
      RECT 0.000000 158.810000 392.160000 162.790000 ;
      RECT 0.000000 157.910000 391.060000 158.810000 ;
      RECT 0.000000 157.590000 392.160000 157.910000 ;
      RECT 0.000000 156.980000 391.060000 157.590000 ;
      RECT 1.100000 156.690000 391.060000 156.980000 ;
      RECT 1.100000 156.080000 392.160000 156.690000 ;
      RECT 0.000000 154.540000 392.160000 156.080000 ;
      RECT 1.100000 153.640000 392.160000 154.540000 ;
      RECT 0.000000 150.880000 392.160000 153.640000 ;
      RECT 0.000000 149.980000 391.060000 150.880000 ;
      RECT 0.000000 143.560000 392.160000 149.980000 ;
      RECT 1.100000 142.660000 391.060000 143.560000 ;
      RECT 0.000000 138.070000 392.160000 142.660000 ;
      RECT 1.100000 137.460000 392.160000 138.070000 ;
      RECT 1.100000 137.170000 391.060000 137.460000 ;
      RECT 0.000000 136.560000 391.060000 137.170000 ;
      RECT 0.000000 125.260000 392.160000 136.560000 ;
      RECT 0.000000 124.650000 391.060000 125.260000 ;
      RECT 1.100000 124.360000 391.060000 124.650000 ;
      RECT 1.100000 123.750000 392.160000 124.360000 ;
      RECT 0.000000 117.330000 392.160000 123.750000 ;
      RECT 0.000000 116.430000 391.060000 117.330000 ;
      RECT 0.000000 111.230000 392.160000 116.430000 ;
      RECT 1.100000 110.330000 392.160000 111.230000 ;
      RECT 0.000000 109.400000 392.160000 110.330000 ;
      RECT 0.000000 108.500000 391.060000 109.400000 ;
      RECT 0.000000 108.180000 392.160000 108.500000 ;
      RECT 0.000000 107.280000 391.060000 108.180000 ;
      RECT 0.000000 106.960000 392.160000 107.280000 ;
      RECT 0.000000 106.060000 391.060000 106.960000 ;
      RECT 0.000000 0.000000 392.160000 106.060000 ;
    LAYER met4 ;
      RECT 232.545000 385.920000 392.160000 387.020000 ;
      RECT 221.475000 385.920000 231.645000 387.020000 ;
      RECT 218.400000 385.920000 220.575000 387.020000 ;
      RECT 214.710000 385.920000 217.500000 387.020000 ;
      RECT 212.865000 385.920000 213.810000 387.020000 ;
      RECT 161.205000 385.920000 211.965000 387.020000 ;
      RECT 0.000000 385.920000 160.305000 387.020000 ;
      RECT 0.000000 1.100000 392.160000 385.920000 ;
      RECT 300.810000 0.000000 392.160000 1.100000 ;
      RECT 278.670000 0.000000 299.910000 1.100000 ;
      RECT 233.160000 0.000000 277.770000 1.100000 ;
      RECT 231.930000 0.000000 232.260000 1.100000 ;
      RECT 230.700000 0.000000 231.030000 1.100000 ;
      RECT 224.550000 0.000000 229.800000 1.100000 ;
      RECT 222.090000 0.000000 223.650000 1.100000 ;
      RECT 219.630000 0.000000 221.190000 1.100000 ;
      RECT 217.170000 0.000000 218.730000 1.100000 ;
      RECT 215.325000 0.000000 216.270000 1.100000 ;
      RECT 214.095000 0.000000 214.425000 1.100000 ;
      RECT 174.735000 0.000000 213.195000 1.100000 ;
      RECT 163.050000 0.000000 173.835000 1.100000 ;
      RECT 151.365000 0.000000 162.150000 1.100000 ;
      RECT 0.000000 0.000000 150.465000 1.100000 ;
    LAYER met5 ;
      RECT 0.000000 288.250000 392.160000 387.020000 ;
      RECT 0.000000 283.450000 388.060000 288.250000 ;
      RECT 0.000000 273.610000 392.160000 283.450000 ;
      RECT 4.100000 268.810000 392.160000 273.610000 ;
      RECT 0.000000 251.650000 392.160000 268.810000 ;
      RECT 0.000000 246.850000 388.060000 251.650000 ;
      RECT 0.000000 233.350000 392.160000 246.850000 ;
      RECT 0.000000 228.550000 388.060000 233.350000 ;
      RECT 0.000000 226.030000 392.160000 228.550000 ;
      RECT 0.000000 222.370000 388.060000 226.030000 ;
      RECT 4.100000 221.230000 388.060000 222.370000 ;
      RECT 4.100000 217.570000 392.160000 221.230000 ;
      RECT 0.000000 127.210000 392.160000 217.570000 ;
      RECT 4.100000 122.410000 392.160000 127.210000 ;
      RECT 0.000000 0.000000 392.160000 122.410000 ;
  END
END mdu_macro

END LIBRARY
